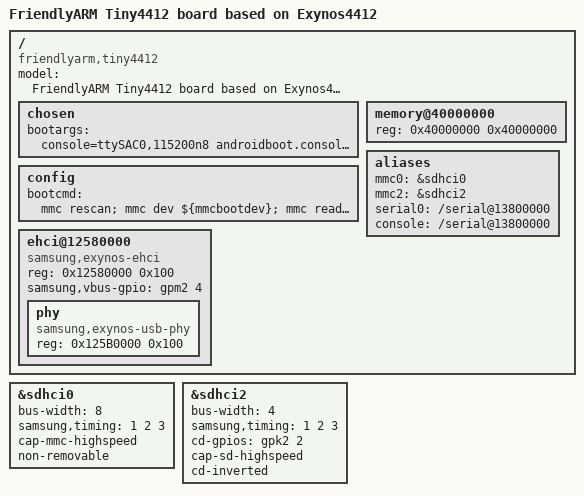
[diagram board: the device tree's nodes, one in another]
// SPDX-License-Identifier: GPL-2.0+
/*
 * Samsung's Exynos4412 based Tiny4412 board device tree source
 *
 * Copyright (c) 2014 Samsung Electronics Co., Ltd.
 *		http://www.samsung.com
 */

/dts-v1/;
#include "skeleton.dtsi"
#include "exynos4412.dtsi"

/ {
	model = "FriendlyARM Tiny4412 board based on Exynos4412";
	compatible = "friendlyarm,tiny4412", "samsung,tiny4412", "samsung,exynos4412";

	chosen {
		bootargs ="console=ttySAC0,115200n8 androidboot.console=ttySAC0 ctp=1 skipcali=y ethmac=1C:6F:65:34:51:7E androidboot.selinux=permissive mem=512M";
	};

	config {
		bootcmd = "mmc rescan; mmc dev ${mmcbootdev}; \
			mmc read ${kernelloadaddr} ${kernelboff} ${kernelbsize}; \
			mmc read ${ramdiskloadaddr} ${ramdiskboff} ${ramdiskbsize}; \
			setenv initrd_high 0xffffffff; \
			bootz ${kernelloadaddr} ${ramdiskloadaddr}";
	};

	memory@40000000 {
		device_type = "memory";
		reg = <0x40000000 0x40000000>;
	};

	aliases {
		mmc0 = &sdhci0;
		mmc2 = &sdhci2;
		serial0 = "/serial@13800000";
		console = "/serial@13800000";
	};

	ehci@12580000 {
		compatible = "samsung,exynos-ehci";
		reg = <0x12580000 0x100>;
		#address-cells = <1>;
		#size-cells = <1>;
		status = "okay";
		/* GPM2_4_USBRST resets USB4640 hub and DM9621 */
		samsung,vbus-gpio = <&gpm2 4 0>;
		phy {
			compatible = "samsung,exynos-usb-phy";
			reg = <0x125B0000 0x100>;
		};
	};

};


&sdhci0 {
	bus-width = <8>;
	samsung,timing = <1 2 3>;
	cap-mmc-highspeed;
	non-removable;
	status = "okay";
};


&sdhci2 {
	bus-width = <4>;
	samsung,timing = <1 2 3>;
	cd-gpios = <&gpk2 2 0>;
	cap-sd-highspeed;
	cd-inverted;
	status = "okay";
};
